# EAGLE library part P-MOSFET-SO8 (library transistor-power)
P-Channel MOSFET Example: FDS4435A; P-Channel Logic Level PowerTrench® MOSFET FDS4465; P-Channel 1.8V Specified PowerTrench® MOSFET Source: www.fairchildsemi.com

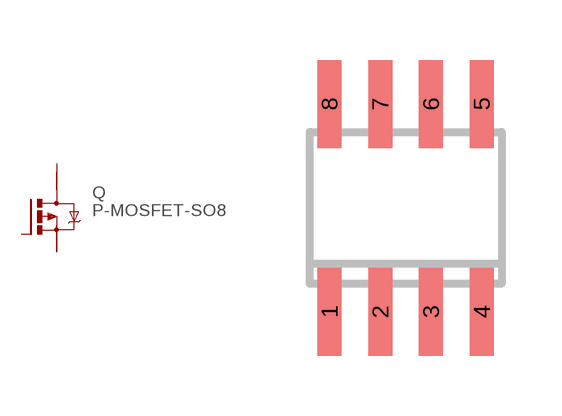
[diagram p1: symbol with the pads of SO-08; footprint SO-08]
Designator prefix Q

## P-MOSFET-SO8  [SO-08]
1  S  pas
2  S  pas
3  S  pas
4  G  pas
5  D  pas
6  D  pas
7  D  pas
8  D  pas

## Footprint SO-08 (pad centres in mm)
Small Outline Narrow Plastic Gull Wing 150-mil body, package type SN
smd 0.6 x 2.2: 1 -1.905,-2.6; 2 -0.635,-2.6; 3 0.635,-2.6; 4 1.905,-2.6; 5 1.905,2.6; 6 0.635,2.6; 7 -0.635,2.6; 8 -1.905,2.6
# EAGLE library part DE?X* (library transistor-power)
RF Power MOSFET Common Source Push-Pull Pair Source: http://ixysrf.com/pdf/switch_mode/de275x2_501n16a.pdf

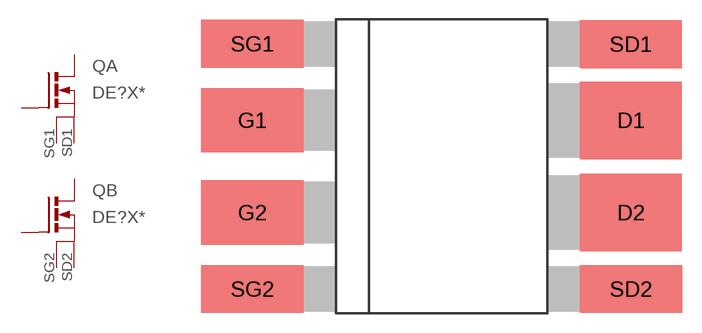
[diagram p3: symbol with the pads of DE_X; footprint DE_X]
Designator prefix Q; gates A=DE_2-MOSFET B=DE_2-MOSFET

## DE275X2-102N06A, DE275X2-501N16A  [DE_X]
D1  A:D  pas
D2  B:D  pas
G1  A:G  pas
G2  B:G  pas
SD1  A:SD  pas
SD2  B:SD  pas
SG1  A:SG  pas
SG2  B:SG  pas

## Footprint DE_X (pad centres in mm)
DE-Type Power MOSFET Package Source: http://ixysrf.com/pdf/switch_mode/de275x2_501n16a.pdf
smd 7.874 x 5.969: D1 14.592,3.556; D2 14.592,-3.556
smd 7.874 x 4.953: G1 -14.592,3.556; G2 -14.592,-3.556
smd 7.874 x 3.683: SD1 14.592,9.423; SD2 14.605,-9.449; SG1 -14.592,9.449; SG2 -14.592,-9.449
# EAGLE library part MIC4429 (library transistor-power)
6A-Peak Low-Side MOSFET Driver (INVERTED) Bipolar/CMOS/DMOS Process http://www.micrel.com/_PDF/mic4420.pdf

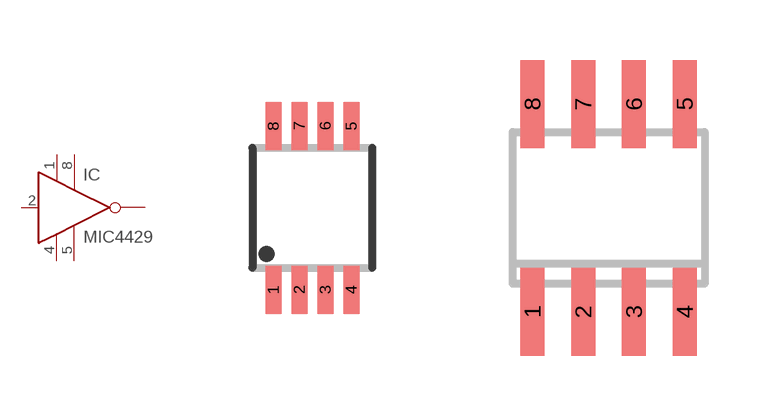
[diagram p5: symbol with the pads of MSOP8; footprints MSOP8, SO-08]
Designator prefix IC

## MIC4429MM  [MSOP8]
1  VS  pwr
2  IN  in
4  GND  pwr
5  GND1  pwr
6  OUT  pas
7  OUT  pas
8  VS1  pwr

## MIC4429M  [SO-08]
Pads as for MSOP8

## MIC4429N  [DIL08]
Pads as for MSOP8

## Footprint MSOP8 (pad centres in mm)
MSOP8
smd 0.4 x 1.2: 1 -0.975,-2.05; 2 -0.325,-2.05; 3 0.325,-2.05; 4 0.975,-2.05; 5 0.975,2.05; 6 0.325,2.05; 7 -0.325,2.05; 8 -0.975,2.05

## Footprint SO-08 (pad centres in mm)
Small Outline Narrow Plastic Gull Wing 150-mil body, package type SN
smd 0.6 x 2.2: 1 -1.905,-2.6; 2 -0.635,-2.6; 3 0.635,-2.6; 4 1.905,-2.6; 5 1.905,2.6; 6 0.635,2.6; 7 -0.635,2.6; 8 -1.905,2.6

## Footprint DIL08 (pad centres in mm)
Dual In Line Package
drill 0.813 long: 1 -3.81,-3.81; 2 -1.27,-3.81; 3 1.27,-3.81; 4 3.81,-3.81; 5 3.81,3.81; 6 1.27,3.81; 7 -1.27,3.81; 8 -3.81,3.81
